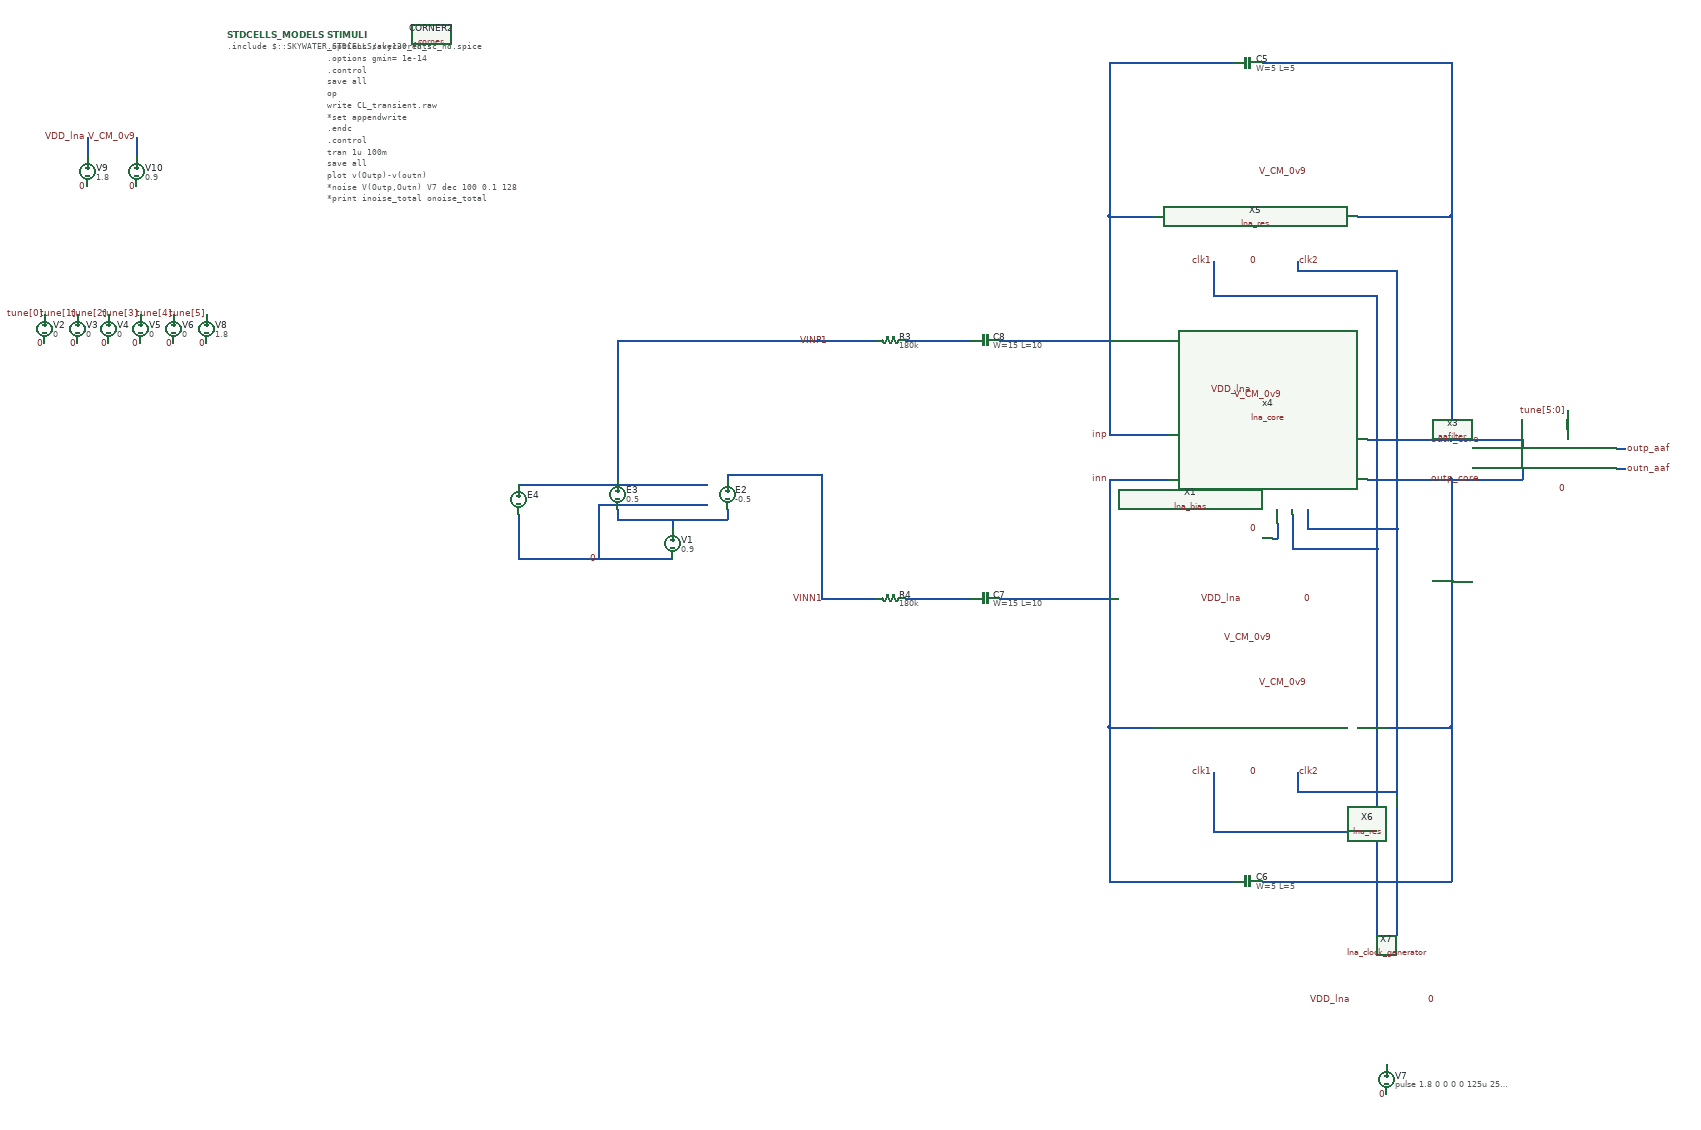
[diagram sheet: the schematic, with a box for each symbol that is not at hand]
v {xschem version=3.1.0 file_version=1.2
}
G {}
K {}
V {}
S {}
E {}
N 1360 -1450 1470 -1450 {
lab=inp}
N 1360 -1360 1470 -1360 {
lab=inn}
N 1880 -1440 2040 -1440 {
lab=outn_core}
N 2040 -1890 2040 -1440 {
lab=outn_core}
N 1850 -1890 2040 -1890 {
lab=outn_core}
N 1350 -1890 1440 -1890 {
lab=inp}
N 1350 -1890 1350 -1450 {
lab=inp}
N 1350 -1450 1360 -1450 {
lab=inp}
N 1870 -1360 2040 -1360 {
lab=outp_core}
N 1850 -860 2040 -860 {
lab=outp_core}
N 1350 -860 1440 -860 {
lab=inn}
N 2040 -1360 2040 -910 {
lab=outp_core}
N 1350 -1360 1350 -920 {
lab=inn}
N 1350 -1360 1360 -1360 {
lab=inn}
N 1350 -920 1350 -860 {
lab=inn}
N 2040 -910 2040 -860 {
lab=outp_core}
N -710 -2050 -710 -2010 {
lab=VDD_lna}
N -610 -2050 -610 -2010 {
lab=V_CM_0v9}
N 1360 -2200 1600 -2200 {
lab=inp}
N 1350 -2200 1350 -1890 {
lab=inp}
N 1350 -2200 1360 -2200 {
lab=inp}
N 1660 -2200 2040 -2200 {
lab=outn_core}
N 2040 -2200 2040 -1890 {
lab=outn_core}
N 1360 -550 1600 -550 {
lab=inn}
N 1350 -550 1360 -550 {
lab=inn}
N 1660 -550 2040 -550 {
lab=outp_core}
N 1350 -860 1350 -550 {
lab=inn}
N 2040 -860 2040 -550 {
lab=outp_core}
N 1130 -1120 1350 -1120 {
lab=inn}
N 1130 -1640 1350 -1640 {
lab=inp}
N 940 -1640 1070 -1640 {
lab=#net1}
N 780 -1640 880 -1640 {
lab=VINP1}
N 940 -1120 1070 -1120 {
lab=#net2}
N 780 -1120 880 -1120 {
lab=VINN1}
N 2040 -1155 2045 -1155 {
lab=outp_core}
N 1870 -1440 1880 -1440 {
lab=outn_core}
N 2040 -1360 2180 -1360 {
lab=outp_core}
N 2040 -1440 2180 -1440 {
lab=outn_core}
N 2183.75 -1440 2183.75 -1421.25 {
lab=outn_core}
N 2180 -1440 2183.75 -1440 {
lab=outn_core}
N 2183.75 -1381.25 2183.75 -1360 {
lab=outp_core}
N 2180 -1360 2183.75 -1360 {
lab=outp_core}
N 2373.75 -1421.25 2391.25 -1421.25 {
lab=outp_aaf}
N 2373.75 -1381.25 2391.25 -1381.25 {
lab=outn_aaf}
N 1720 -1290 1720 -1240 {
lab=clk1}
N 1720 -1220 1860 -1220 {
lab=clk1}
N 1720 -1240 1720 -1220 {
lab=clk1}
N 1750 -1300 1750 -1260 {
lab=clk2}
N 1750 -1260 1900 -1260 {
lab=clk2}
N 1860 -1220 1890 -1220 {
lab=clk1}
N 1900 -1260 1930 -1260 {
lab=clk2}
N 1930 -1260 1930 -1220 {
lab=clk2}
N 1890 -1730 1890 -1220 {
lab=clk1}
N 1560 -770 1560 -650 {
lab=clk1}
N 1560 -650 1890 -650 {
lab=clk1}
N 1730 -770 1730 -730 {
lab=clk2}
N 1730 -730 1930 -730 {
lab=clk2}
N 1930 -730 1930 -680 {
lab=clk2}
N 1930 -680 1930 -440 {
lab=clk2}
N 1890 -1220 1890 -640 {
lab=clk1}
N 1930 -1220 1930 -720 {
lab=clk2}
N 1560 -1730 1890 -1730 {
lab=clk1}
N 1560 -1800 1560 -1730 {
lab=clk1}
N 1730 -1800 1730 -1780 {
lab=clk2}
N 1930 -1780 1930 -1260 {
lab=clk2}
N 1730 -1780 1930 -1780 {
lab=clk2}
N 360 -1300 360 -1280 {
lab=#net3}
N 360 -1280 580 -1280 {
lab=#net3}
N 580 -1300 580 -1280 {
lab=#net3}
N 470 -1280 470 -1260 {
lab=#net3}
N 160 -1200 470 -1200 {
lab=0}
N 160 -1220 160 -1200 {
lab=0}
N 160 -1350 320 -1350 {
lab=#net4}
N 160 -1290 160 -1220 {
lab=0}
N 320 -1310 320 -1200 {
lab=0}
N 580 -1370 580 -1360 {
lab=VINN1}
N 360 -1640 780 -1640 {
lab=VINP1}
N 320 -1350 540 -1350 {
lab=#net4}
N 320 -1310 540 -1310 {
lab=0}
N 770 -1340 770 -1120 {
lab=VINN1}
N 770 -1120 780 -1120 {
lab=VINN1}
N 580 -1370 770 -1370 {
lab=VINN1}
N 770 -1370 770 -1340 {
lab=VINN1}
N 360 -1640 360 -1360 {
lab=VINP1}
N 1890 -640 1890 -440 {
lab=clk1}
N 1680 -1240 1690 -1240 {
lab=#net5}
N 1690 -1270 1690 -1240 {
lab=#net5}
N 2273.75 -1498.75 2273.75 -1461.25 {
lab=tune[5:0]}
C {devices/launcher.sym} -176.25 -2036.25 0 0 {name=h1
descr="Annotate" 
tclcommand="set show_hidden_texts 1; xschem annotate_op"
}
C {sky130_fd_pr/corner.sym} -16.25 -2256.25 0 0 {name=CORNER2 only_toplevel=false corner=tt
}
C {devices/launcher.sym} -176.25 -1976.25 0 0 {name=h2 
descr="Simulate" 
tclcommand="xschem netlist; xschem simulate"}
C {devices/code.sym} -226.25 -2256.25 0 0 {name=STIMULI
only_toplevel=false
value="
.options savecurrents
.options gmin= 1e-14
.control

save all


op
write CL_transient.raw
*set appendwrite


.endc
.control



tran 1u 100m
save all
plot v(Outp)-v(outn)


*noise V(Outp,Outn) V7 dec 100 0.1 128
*print inoise_total onoise_total
*setplot noise1
*plot inoise_spectrum


.endc



"}
C {devices/code.sym} -426.25 -2256.25 0 0 {name=STDCELLS_MODELS
only_toplevel=true
format="tcleval( @value )"
value="
.include $::SKYWATER_STDCELLS/sky130_fd_sc_hd.spice
"
spice_ignore=false}
C {LNA/lna_core.sym} 1580 -1510 0 0 {name=x4}
C {sky130_fd_pr/cap_mim_m3_2.sym} 1630 -2200 3 0 {name=C5 model=cap_mim_m3_2 W=5 L=5 MF=19 spiceprefix=X}
C {LNA/lna_res.sym} 1650 -1890 0 0 {name=X5}
C {LNA/lna_res.sym} 1650 -860 0 0 {name=X6}
C {devices/lab_pin.sym} 1650 -770 3 0 {name=p18 sig_type=std_logic lab=0}
C {devices/lab_pin.sym} 1650 -1800 3 0 {name=p22 sig_type=std_logic lab=0}
C {devices/vsource.sym} 1910 -150 0 0 {name=V7 value="pulse 1.8 0 0 0 0 125u 250u"}
C {LNA/lna_clock_generator.sym} 1910 -310 3 0 {name=X7}
C {devices/lab_pin.sym} 1990 -310 2 0 {name=p31 sig_type=std_logic lab=0}
C {devices/lab_pin.sym} 1840 -310 0 0 {name=p32 sig_type=std_logic lab=VDD_lna}
C {devices/lab_pin.sym} 1650 -1260 3 0 {name=p36 sig_type=std_logic lab=0}
C {devices/lab_pin.sym} 1640 -1540 1 0 {name=p37 sig_type=std_logic lab=VDD_lna}
C {devices/lab_pin.sym} 1560 -770 0 0 {name=p38 sig_type=std_logic lab=clk1}
C {devices/lab_pin.sym} 1730 -770 2 0 {name=p39 sig_type=std_logic lab=clk2}
C {devices/lab_pin.sym} 1560 -1800 0 0 {name=p46 sig_type=std_logic lab=clk1}
C {devices/lab_pin.sym} 1730 -1800 2 0 {name=p47 sig_type=std_logic lab=clk2}
C {devices/vsource.sym} -710 -1980 0 0 {name=V9 value="1.8"}
C {devices/lab_pin.sym} -710 -1950 3 0 {name=p49 sig_type=std_logic lab=0}
C {devices/lab_pin.sym} -710 -2050 1 0 {name=p50 sig_type=std_logic lab=VDD_lna}
C {devices/vsource.sym} -610 -1980 0 0 {name=V10 value="0.9"}
C {devices/lab_pin.sym} -610 -1950 3 0 {name=p51 sig_type=std_logic lab=0}
C {devices/lab_pin.sym} -610 -2050 1 0 {name=p52 sig_type=std_logic lab=V_CM_0v9}
C {devices/lab_pin.sym} 1700 -1530 1 0 {name=p53 sig_type=std_logic lab=V_CM_0v9}
C {devices/lab_pin.sym} 1650 -950 2 0 {name=p54 sig_type=std_logic lab=V_CM_0v9}
C {devices/lab_pin.sym} 1650 -1980 2 0 {name=p48 sig_type=std_logic lab=V_CM_0v9}
C {sky130_fd_pr/cap_mim_m3_2.sym} 1630 -550 3 0 {name=C6 model=cap_mim_m3_2 W=5 L=5 MF=19 spiceprefix=X}
C {sky130_fd_pr/cap_mim_m3_2.sym} 1100 -1120 1 1 {name=C7 model=cap_mim_m3_1 W=15 L=10 MF=1500 spiceprefix=X}
C {sky130_fd_pr/cap_mim_m3_2.sym} 1100 -1640 1 1 {name=C8 model=cap_mim_m3_1 W=15 L=10 MF=1500 spiceprefix=X}
C {devices/res.sym} 910 -1640 1 0 {name=R3
value=180k
footprint=1206
device=resistor
m=1}
C {devices/res.sym} 910 -1120 1 0 {name=R4
value=180k
footprint=1206
device=resistor
m=1}
C {devices/lab_pin.sym} 775 -1120 2 1 {name=p55 sig_type=std_logic lab=VINN1}
C {devices/lab_pin.sym} 785 -1640 3 1 {name=p56 sig_type=std_logic lab=VINP1}
C {devices/lab_pin.sym} 2100 -1440 1 0 {name=p1 sig_type=std_logic lab=outn_core}
C {devices/lab_pin.sym} 2100 -1360 3 0 {name=p2 sig_type=std_logic lab=outp_core}
C {devices/lab_pin.sym} 1350 -1450 0 0 {name=p3 sig_type=std_logic lab=inp}
C {devices/lab_pin.sym} 1350 -1360 0 0 {name=p4 sig_type=std_logic lab=inn}
C {devices/title.sym} 1210 -20 0 0 {name=l2 author="Amirhossein Zanjani"}
C {devices/lab_pin.sym} 1680 -1040 0 0 {name=p9 sig_type=std_logic lab=V_CM_0v9}
C {devices/lab_pin.sym} 1740 -1120 2 0 {name=p10 sig_type=std_logic lab=0}
C {devices/lab_pin.sym} 1620 -1120 0 0 {name=p11 sig_type=std_logic lab=VDD_lna}
C {LNA/aafilter.sym} 2203.75 -1441.25 0 0 {name=x3}
C {devices/lab_pin.sym} 2273.75 -1341.25 3 0 {name=p7 sig_type=std_logic lab=0}
C {LNA/lna_bias.sym} 1640 -1080 3 0 {name=X1}
C {devices/lab_pin.sym} 1910 -120 3 0 {name=p6 sig_type=std_logic lab=0}
C {devices/vsource.sym} 470 -1230 0 0 {name=V1 value=0.9}
C {devices/vcvs.sym} 580 -1330 0 0 {name=E2 value=-0.5}
C {devices/vcvs.sym} 360 -1330 0 0 {name=E3 value=0.5}
C {devices/lab_pin.sym} 320 -1200 3 0 {name=p5 sig_type=std_logic lab=0}
C {devices/vsource_arith.sym} 160 -1320 0 0 {name=E4 VOL="'0.001*cos(2*pi*time*1e2)'"}
C {devices/lab_pin.sym} 2273.75 -1497.5 1 0 {name=p20 sig_type=std_logic lab=tune[5:0]}
C {devices/lab_pin.sym} 2391.25 -1421.25 2 0 {name=p14 sig_type=std_logic lab=outp_aaf}
C {devices/lab_pin.sym} 2391.25 -1381.25 2 0 {name=p15 sig_type=std_logic lab=outn_aaf}
C {devices/lab_pin.sym} -795.625 -1693.125 1 0 {name=p21 sig_type=std_logic lab=tune[0]}
C {devices/vsource.sym} -795.625 -1663.125 0 0 {name=V2 value="0"}
C {devices/lab_pin.sym} -795.625 -1633.125 3 0 {name=p23 sig_type=std_logic lab=0}
C {devices/vsource.sym} -729.375 -1663.125 0 0 {name=V3 value="0"}
C {devices/lab_pin.sym} -729.375 -1633.125 3 0 {name=p24 sig_type=std_logic lab=0}
C {devices/vsource.sym} -666.875 -1663.125 0 0 {name=V4 value="0"}
C {devices/lab_pin.sym} -666.875 -1633.125 3 0 {name=p25 sig_type=std_logic lab=0}
C {devices/vsource.sym} -603.125 -1663.125 0 0 {name=V5 value="0"}
C {devices/lab_pin.sym} -603.125 -1633.125 3 0 {name=p26 sig_type=std_logic lab=0}
C {devices/vsource.sym} -535.625 -1663.125 0 0 {name=V6 value="0"}
C {devices/lab_pin.sym} -535.625 -1633.125 3 0 {name=p27 sig_type=std_logic lab=0}
C {devices/vsource.sym} -468.75 -1663.125 0 0 {name=V8 value="1.8"}
C {devices/lab_pin.sym} -468.75 -1633.125 3 0 {name=p28 sig_type=std_logic lab=0}
C {devices/lab_pin.sym} -729.375 -1693.125 1 0 {name=p29 sig_type=std_logic lab=tune[1]}
C {devices/lab_pin.sym} -666.875 -1693.125 1 0 {name=p30 sig_type=std_logic lab=tune[2]}
C {devices/lab_pin.sym} -603.125 -1693.125 1 0 {name=p33 sig_type=std_logic lab=tune[3]}
C {devices/lab_pin.sym} -535.625 -1693.125 1 0 {name=p34 sig_type=std_logic lab=tune[4]}
C {devices/lab_pin.sym} -468.75 -1693.125 1 0 {name=p35 sig_type=std_logic lab=tune[5]}
